VERSION 5.7 ;
  NOWIREEXTENSIONATPIN ON ;
  DIVIDERCHAR "/" ;
  BUSBITCHARS "[]" ;
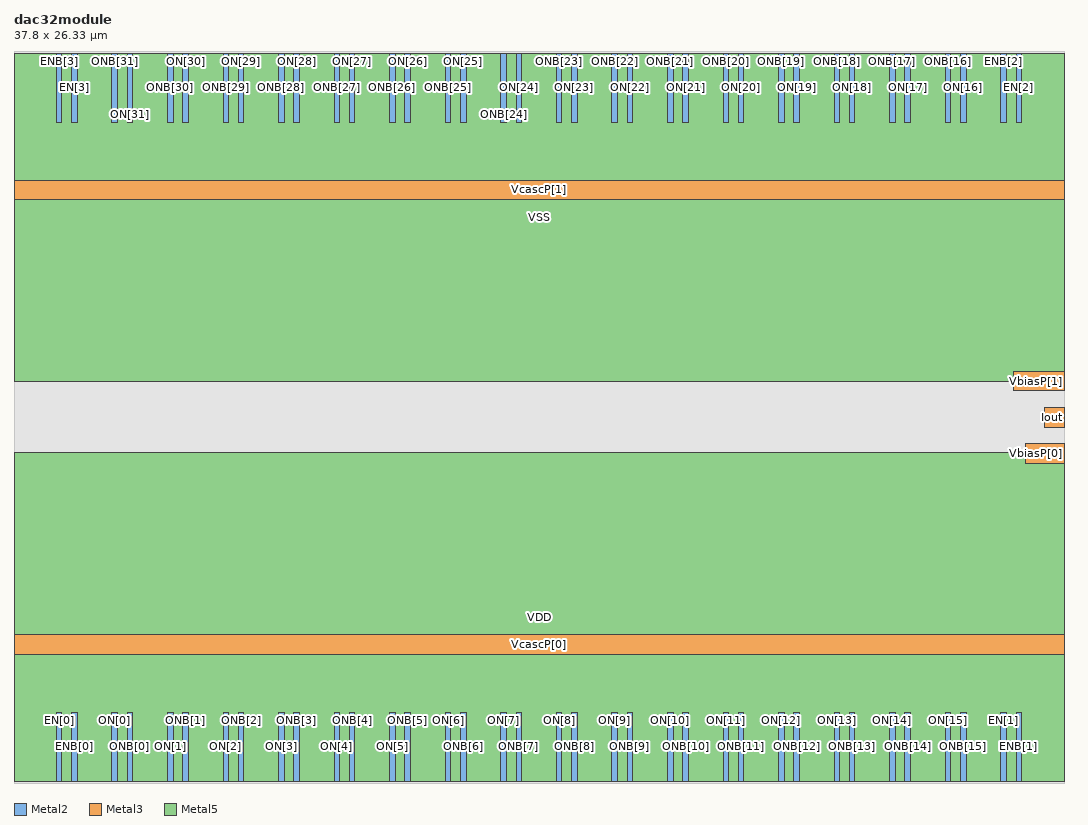
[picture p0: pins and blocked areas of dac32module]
MACRO dac32module
  CLASS BLOCK ;
  FOREIGN dac32module ;
  ORIGIN 0.000 0.070 ;
  SIZE 37.800 BY 26.330 ;
  PIN EN[1]
    ANTENNAGATEAREA 0.039000 ;
    PORT
      LAYER Metal2 ;
        RECT 35.525 0.000 35.725 2.475 ;
    END
  END EN[1]
  PIN ENB[1]
    ANTENNAGATEAREA 0.039000 ;
    PORT
      LAYER Metal2 ;
        RECT 36.075 0.000 36.275 2.475 ;
    END
  END ENB[1]
  PIN EN[2]
    ANTENNAGATEAREA 0.039000 ;
    PORT
      LAYER Metal2 ;
        RECT 36.075 23.715 36.275 26.190 ;
    END
  END EN[2]
  PIN ENB[2]
    ANTENNAGATEAREA 0.039000 ;
    PORT
      LAYER Metal2 ;
        RECT 35.525 23.715 35.725 26.190 ;
    END
  END ENB[2]
  PIN ON[16]
    ANTENNAGATEAREA 0.039000 ;
    PORT
      LAYER Metal2 ;
        RECT 34.075 23.715 34.275 26.190 ;
    END
  END ON[16]
  PIN ONB[16]
    ANTENNAGATEAREA 0.039000 ;
    PORT
      LAYER Metal2 ;
        RECT 33.525 23.715 33.725 26.190 ;
    END
  END ONB[16]
  PIN ON[17]
    ANTENNAGATEAREA 0.039000 ;
    PORT
      LAYER Metal2 ;
        RECT 32.075 23.715 32.275 26.190 ;
    END
  END ON[17]
  PIN ONB[17]
    ANTENNAGATEAREA 0.039000 ;
    PORT
      LAYER Metal2 ;
        RECT 31.525 23.715 31.725 26.190 ;
    END
  END ONB[17]
  PIN ON[18]
    ANTENNAGATEAREA 0.039000 ;
    PORT
      LAYER Metal2 ;
        RECT 30.075 23.715 30.275 26.190 ;
    END
  END ON[18]
  PIN ONB[18]
    ANTENNAGATEAREA 0.039000 ;
    PORT
      LAYER Metal2 ;
        RECT 29.525 23.715 29.725 26.190 ;
    END
  END ONB[18]
  PIN ON[19]
    ANTENNAGATEAREA 0.039000 ;
    PORT
      LAYER Metal2 ;
        RECT 28.075 23.715 28.275 26.190 ;
    END
  END ON[19]
  PIN ONB[19]
    ANTENNAGATEAREA 0.039000 ;
    PORT
      LAYER Metal2 ;
        RECT 27.525 23.715 27.725 26.190 ;
    END
  END ONB[19]
  PIN ON[20]
    ANTENNAGATEAREA 0.039000 ;
    PORT
      LAYER Metal2 ;
        RECT 26.075 23.715 26.275 26.190 ;
    END
  END ON[20]
  PIN ONB[20]
    ANTENNAGATEAREA 0.039000 ;
    PORT
      LAYER Metal2 ;
        RECT 25.525 23.715 25.725 26.190 ;
    END
  END ONB[20]
  PIN ON[21]
    ANTENNAGATEAREA 0.039000 ;
    PORT
      LAYER Metal2 ;
        RECT 24.075 23.715 24.275 26.190 ;
    END
  END ON[21]
  PIN ONB[21]
    ANTENNAGATEAREA 0.039000 ;
    PORT
      LAYER Metal2 ;
        RECT 23.525 23.715 23.725 26.190 ;
    END
  END ONB[21]
  PIN ON[22]
    ANTENNAGATEAREA 0.039000 ;
    PORT
      LAYER Metal2 ;
        RECT 22.075 23.715 22.275 26.190 ;
    END
  END ON[22]
  PIN ONB[22]
    ANTENNAGATEAREA 0.039000 ;
    PORT
      LAYER Metal2 ;
        RECT 21.525 23.715 21.725 26.190 ;
    END
  END ONB[22]
  PIN ON[23]
    ANTENNAGATEAREA 0.039000 ;
    PORT
      LAYER Metal2 ;
        RECT 20.075 23.715 20.275 26.190 ;
    END
  END ON[23]
  PIN ONB[23]
    ANTENNAGATEAREA 0.039000 ;
    PORT
      LAYER Metal2 ;
        RECT 19.525 23.715 19.725 26.190 ;
    END
  END ONB[23]
  PIN ON[24]
    ANTENNAGATEAREA 0.039000 ;
    PORT
      LAYER Metal2 ;
        RECT 18.075 23.715 18.275 26.190 ;
    END
  END ON[24]
  PIN ONB[24]
    ANTENNAGATEAREA 0.039000 ;
    PORT
      LAYER Metal2 ;
        RECT 17.525 23.715 17.725 26.190 ;
    END
  END ONB[24]
  PIN ON[25]
    ANTENNAGATEAREA 0.039000 ;
    PORT
      LAYER Metal2 ;
        RECT 16.075 23.715 16.275 26.190 ;
    END
  END ON[25]
  PIN ONB[25]
    ANTENNAGATEAREA 0.039000 ;
    PORT
      LAYER Metal2 ;
        RECT 15.525 23.715 15.725 26.190 ;
    END
  END ONB[25]
  PIN ON[26]
    ANTENNAGATEAREA 0.039000 ;
    PORT
      LAYER Metal2 ;
        RECT 14.075 23.715 14.275 26.190 ;
    END
  END ON[26]
  PIN ONB[26]
    ANTENNAGATEAREA 0.039000 ;
    PORT
      LAYER Metal2 ;
        RECT 13.525 23.715 13.725 26.190 ;
    END
  END ONB[26]
  PIN ON[27]
    ANTENNAGATEAREA 0.039000 ;
    PORT
      LAYER Metal2 ;
        RECT 12.075 23.715 12.275 26.190 ;
    END
  END ON[27]
  PIN ONB[27]
    ANTENNAGATEAREA 0.039000 ;
    PORT
      LAYER Metal2 ;
        RECT 11.525 23.715 11.725 26.190 ;
    END
  END ONB[27]
  PIN ON[28]
    ANTENNAGATEAREA 0.039000 ;
    PORT
      LAYER Metal2 ;
        RECT 10.075 23.715 10.275 26.190 ;
    END
  END ON[28]
  PIN ONB[28]
    ANTENNAGATEAREA 0.039000 ;
    PORT
      LAYER Metal2 ;
        RECT 9.525 23.715 9.725 26.190 ;
    END
  END ONB[28]
  PIN ON[29]
    ANTENNAGATEAREA 0.039000 ;
    PORT
      LAYER Metal2 ;
        RECT 8.075 23.715 8.275 26.190 ;
    END
  END ON[29]
  PIN ONB[29]
    ANTENNAGATEAREA 0.039000 ;
    PORT
      LAYER Metal2 ;
        RECT 7.525 23.715 7.725 26.190 ;
    END
  END ONB[29]
  PIN ON[30]
    ANTENNAGATEAREA 0.039000 ;
    PORT
      LAYER Metal2 ;
        RECT 6.075 23.715 6.275 26.190 ;
    END
  END ON[30]
  PIN ONB[30]
    ANTENNAGATEAREA 0.039000 ;
    PORT
      LAYER Metal2 ;
        RECT 5.525 23.715 5.725 26.190 ;
    END
  END ONB[30]
  PIN ON[31]
    ANTENNAGATEAREA 0.039000 ;
    PORT
      LAYER Metal2 ;
        RECT 4.075 23.715 4.275 26.190 ;
    END
  END ON[31]
  PIN ONB[31]
    ANTENNAGATEAREA 0.039000 ;
    PORT
      LAYER Metal2 ;
        RECT 3.525 23.715 3.725 26.190 ;
    END
  END ONB[31]
  PIN EN[3]
    ANTENNAGATEAREA 0.039000 ;
    PORT
      LAYER Metal2 ;
        RECT 2.075 23.715 2.275 26.190 ;
    END
  END EN[3]
  PIN ENB[3]
    ANTENNAGATEAREA 0.039000 ;
    PORT
      LAYER Metal2 ;
        RECT 1.525 23.715 1.725 26.190 ;
    END
  END ENB[3]
  PIN ON[0]
    ANTENNAGATEAREA 0.039000 ;
    PORT
      LAYER Metal2 ;
        RECT 3.525 0.000 3.725 2.475 ;
    END
  END ON[0]
  PIN ONB[0]
    ANTENNAGATEAREA 0.039000 ;
    PORT
      LAYER Metal2 ;
        RECT 4.075 0.000 4.275 2.475 ;
    END
  END ONB[0]
  PIN ON[1]
    ANTENNAGATEAREA 0.039000 ;
    PORT
      LAYER Metal2 ;
        RECT 5.525 0.000 5.725 2.475 ;
    END
  END ON[1]
  PIN ONB[1]
    ANTENNAGATEAREA 0.039000 ;
    PORT
      LAYER Metal2 ;
        RECT 6.075 0.000 6.275 2.475 ;
    END
  END ONB[1]
  PIN ON[2]
    ANTENNAGATEAREA 0.039000 ;
    PORT
      LAYER Metal2 ;
        RECT 7.525 0.000 7.725 2.475 ;
    END
  END ON[2]
  PIN ONB[2]
    ANTENNAGATEAREA 0.039000 ;
    PORT
      LAYER Metal2 ;
        RECT 8.075 0.000 8.275 2.475 ;
    END
  END ONB[2]
  PIN ON[3]
    ANTENNAGATEAREA 0.039000 ;
    PORT
      LAYER Metal2 ;
        RECT 9.525 0.000 9.725 2.475 ;
    END
  END ON[3]
  PIN ONB[3]
    ANTENNAGATEAREA 0.039000 ;
    PORT
      LAYER Metal2 ;
        RECT 10.075 0.000 10.275 2.475 ;
    END
  END ONB[3]
  PIN ON[4]
    ANTENNAGATEAREA 0.039000 ;
    PORT
      LAYER Metal2 ;
        RECT 11.525 0.000 11.725 2.475 ;
    END
  END ON[4]
  PIN ONB[4]
    ANTENNAGATEAREA 0.039000 ;
    PORT
      LAYER Metal2 ;
        RECT 12.075 0.000 12.275 2.475 ;
    END
  END ONB[4]
  PIN ON[5]
    ANTENNAGATEAREA 0.039000 ;
    PORT
      LAYER Metal2 ;
        RECT 13.525 0.000 13.725 2.475 ;
    END
  END ON[5]
  PIN ONB[5]
    ANTENNAGATEAREA 0.039000 ;
    PORT
      LAYER Metal2 ;
        RECT 14.075 0.000 14.275 2.475 ;
    END
  END ONB[5]
  PIN ON[6]
    ANTENNAGATEAREA 0.039000 ;
    PORT
      LAYER Metal2 ;
        RECT 15.525 0.000 15.725 2.475 ;
    END
  END ON[6]
  PIN EN[0]
    ANTENNAGATEAREA 0.039000 ;
    PORT
      LAYER Metal2 ;
        RECT 1.525 0.000 1.725 2.475 ;
    END
  END EN[0]
  PIN ENB[0]
    ANTENNAGATEAREA 0.039000 ;
    PORT
      LAYER Metal2 ;
        RECT 2.075 0.000 2.275 2.475 ;
    END
  END ENB[0]
  PIN ONB[6]
    ANTENNAGATEAREA 0.039000 ;
    PORT
      LAYER Metal2 ;
        RECT 16.075 0.000 16.275 2.475 ;
    END
  END ONB[6]
  PIN ON[7]
    ANTENNAGATEAREA 0.039000 ;
    PORT
      LAYER Metal2 ;
        RECT 17.525 0.000 17.725 2.475 ;
    END
  END ON[7]
  PIN ONB[7]
    ANTENNAGATEAREA 0.039000 ;
    PORT
      LAYER Metal2 ;
        RECT 18.075 0.000 18.275 2.475 ;
    END
  END ONB[7]
  PIN ON[8]
    ANTENNAGATEAREA 0.039000 ;
    PORT
      LAYER Metal2 ;
        RECT 19.525 0.000 19.725 2.475 ;
    END
  END ON[8]
  PIN ONB[8]
    ANTENNAGATEAREA 0.039000 ;
    PORT
      LAYER Metal2 ;
        RECT 20.075 0.000 20.275 2.475 ;
    END
  END ONB[8]
  PIN ON[9]
    ANTENNAGATEAREA 0.039000 ;
    PORT
      LAYER Metal2 ;
        RECT 21.525 0.000 21.725 2.475 ;
    END
  END ON[9]
  PIN ONB[9]
    ANTENNAGATEAREA 0.039000 ;
    PORT
      LAYER Metal2 ;
        RECT 22.075 0.000 22.275 2.475 ;
    END
  END ONB[9]
  PIN ON[10]
    ANTENNAGATEAREA 0.039000 ;
    PORT
      LAYER Metal2 ;
        RECT 23.525 0.000 23.725 2.475 ;
    END
  END ON[10]
  PIN ONB[10]
    ANTENNAGATEAREA 0.039000 ;
    PORT
      LAYER Metal2 ;
        RECT 24.075 0.000 24.275 2.475 ;
    END
  END ONB[10]
  PIN ON[11]
    ANTENNAGATEAREA 0.039000 ;
    PORT
      LAYER Metal2 ;
        RECT 25.525 0.000 25.725 2.475 ;
    END
  END ON[11]
  PIN ONB[11]
    ANTENNAGATEAREA 0.039000 ;
    PORT
      LAYER Metal2 ;
        RECT 26.075 0.000 26.275 2.475 ;
    END
  END ONB[11]
  PIN ON[12]
    ANTENNAGATEAREA 0.039000 ;
    PORT
      LAYER Metal2 ;
        RECT 27.525 0.000 27.725 2.475 ;
    END
  END ON[12]
  PIN ONB[12]
    ANTENNAGATEAREA 0.039000 ;
    PORT
      LAYER Metal2 ;
        RECT 28.075 0.000 28.275 2.475 ;
    END
  END ONB[12]
  PIN ON[13]
    ANTENNAGATEAREA 0.039000 ;
    PORT
      LAYER Metal2 ;
        RECT 29.525 0.000 29.725 2.475 ;
    END
  END ON[13]
  PIN ONB[13]
    ANTENNAGATEAREA 0.039000 ;
    PORT
      LAYER Metal2 ;
        RECT 30.075 0.000 30.275 2.475 ;
    END
  END ONB[13]
  PIN ON[14]
    ANTENNAGATEAREA 0.039000 ;
    PORT
      LAYER Metal2 ;
        RECT 31.525 0.000 31.725 2.475 ;
    END
  END ON[14]
  PIN ONB[14]
    ANTENNAGATEAREA 0.039000 ;
    PORT
      LAYER Metal2 ;
        RECT 32.075 0.000 32.275 2.475 ;
    END
  END ONB[14]
  PIN ON[15]
    ANTENNAGATEAREA 0.039000 ;
    PORT
      LAYER Metal2 ;
        RECT 33.525 0.000 33.725 2.475 ;
    END
  END ON[15]
  PIN ONB[15]
    ANTENNAGATEAREA 0.039000 ;
    PORT
      LAYER Metal2 ;
        RECT 34.075 0.000 34.275 2.475 ;
    END
  END ONB[15]
  PIN Iout
    ANTENNADIFFAREA 16.511999 ;
    PORT
      LAYER Metal3 ;
        RECT 37.100 12.745 37.800 13.445 ;
    END
  END Iout
  PIN VbiasP[0]
    ANTENNAGATEAREA 130.500000 ;
    ANTENNADIFFAREA 5.010000 ;
    PORT
      LAYER Metal3 ;
        RECT 36.425 11.445 37.800 12.145 ;
    END
  END VbiasP[0]
  PIN VbiasP[1]
    ANTENNAGATEAREA 130.500000 ;
    ANTENNADIFFAREA 5.010000 ;
    PORT
      LAYER Metal3 ;
        RECT 35.980 14.045 37.800 14.745 ;
    END
  END VbiasP[1]
  PIN VcascP[1]
    ANTENNAGATEAREA 1.755000 ;
    ANTENNADIFFAREA 5.814000 ;
    PORT
      LAYER Metal3 ;
        RECT 0.000 20.930 37.800 21.630 ;
    END
  END VcascP[1]
  PIN VcascP[0]
    ANTENNAGATEAREA 1.755000 ;
    ANTENNADIFFAREA 5.814000 ;
    PORT
      LAYER Metal3 ;
        RECT 0.000 4.560 37.800 5.260 ;
    END
  END VcascP[0]
  PIN VDD
    USE POWER ;
    PORT
      LAYER Metal5 ;
        RECT 0.000 0.000 37.800 11.810 ;
    END
  END VDD
  PIN VSS
    USE GROUND ;
    PORT
      LAYER Metal5 ;
        RECT 0.000 14.380 37.800 26.190 ;
    END
  END VSS
  OBS
      LAYER GatPoly ;
        RECT 0.000 -0.070 37.800 26.260 ;
      LAYER Metal1 ;
        RECT 0.000 0.000 37.800 26.190 ;
      LAYER Metal2 ;
        RECT 0.005 23.505 1.315 26.190 ;
        RECT 2.485 23.505 3.315 26.190 ;
        RECT 4.485 23.505 5.315 26.190 ;
        RECT 6.485 23.505 7.315 26.190 ;
        RECT 8.485 23.505 9.315 26.190 ;
        RECT 10.485 23.505 11.315 26.190 ;
        RECT 12.485 23.505 13.315 26.190 ;
        RECT 14.485 23.505 15.315 26.190 ;
        RECT 16.485 23.505 17.315 26.190 ;
        RECT 18.485 23.505 19.315 26.190 ;
        RECT 20.485 23.505 21.315 26.190 ;
        RECT 22.485 23.505 23.315 26.190 ;
        RECT 24.485 23.505 25.315 26.190 ;
        RECT 26.485 23.505 27.315 26.190 ;
        RECT 28.485 23.505 29.315 26.190 ;
        RECT 30.485 23.505 31.315 26.190 ;
        RECT 32.485 23.505 33.315 26.190 ;
        RECT 34.485 23.505 35.315 26.190 ;
        RECT 36.485 23.505 37.800 26.190 ;
        RECT 0.005 2.685 37.800 23.505 ;
        RECT 0.005 0.000 1.315 2.685 ;
        RECT 2.485 0.000 3.315 2.685 ;
        RECT 4.485 0.000 5.315 2.685 ;
        RECT 6.485 0.000 7.315 2.685 ;
        RECT 8.485 0.000 9.315 2.685 ;
        RECT 10.485 0.000 11.315 2.685 ;
        RECT 12.485 0.000 13.315 2.685 ;
        RECT 14.485 0.000 15.315 2.685 ;
        RECT 16.485 0.000 17.315 2.685 ;
        RECT 18.485 0.000 19.315 2.685 ;
        RECT 20.485 0.000 21.315 2.685 ;
        RECT 22.485 0.000 23.315 2.685 ;
        RECT 24.485 0.000 25.315 2.685 ;
        RECT 26.485 0.000 27.315 2.685 ;
        RECT 28.485 0.000 29.315 2.685 ;
        RECT 30.485 0.000 31.315 2.685 ;
        RECT 32.485 0.000 33.315 2.685 ;
        RECT 34.485 0.000 35.315 2.685 ;
        RECT 36.485 0.000 37.800 2.685 ;
      LAYER Metal3 ;
        RECT 0.000 21.840 37.800 26.190 ;
        RECT 0.000 14.955 37.800 20.720 ;
        RECT 0.000 13.835 35.770 14.955 ;
        RECT 0.000 13.655 37.800 13.835 ;
        RECT 0.000 12.535 36.890 13.655 ;
        RECT 0.000 12.355 37.800 12.535 ;
        RECT 0.000 11.235 36.215 12.355 ;
        RECT 0.000 5.470 37.800 11.235 ;
        RECT 0.000 0.000 37.800 4.350 ;
      LAYER Metal4 ;
        RECT 0.000 0.000 37.800 26.190 ;
  END
END dac32module
END LIBRARY

